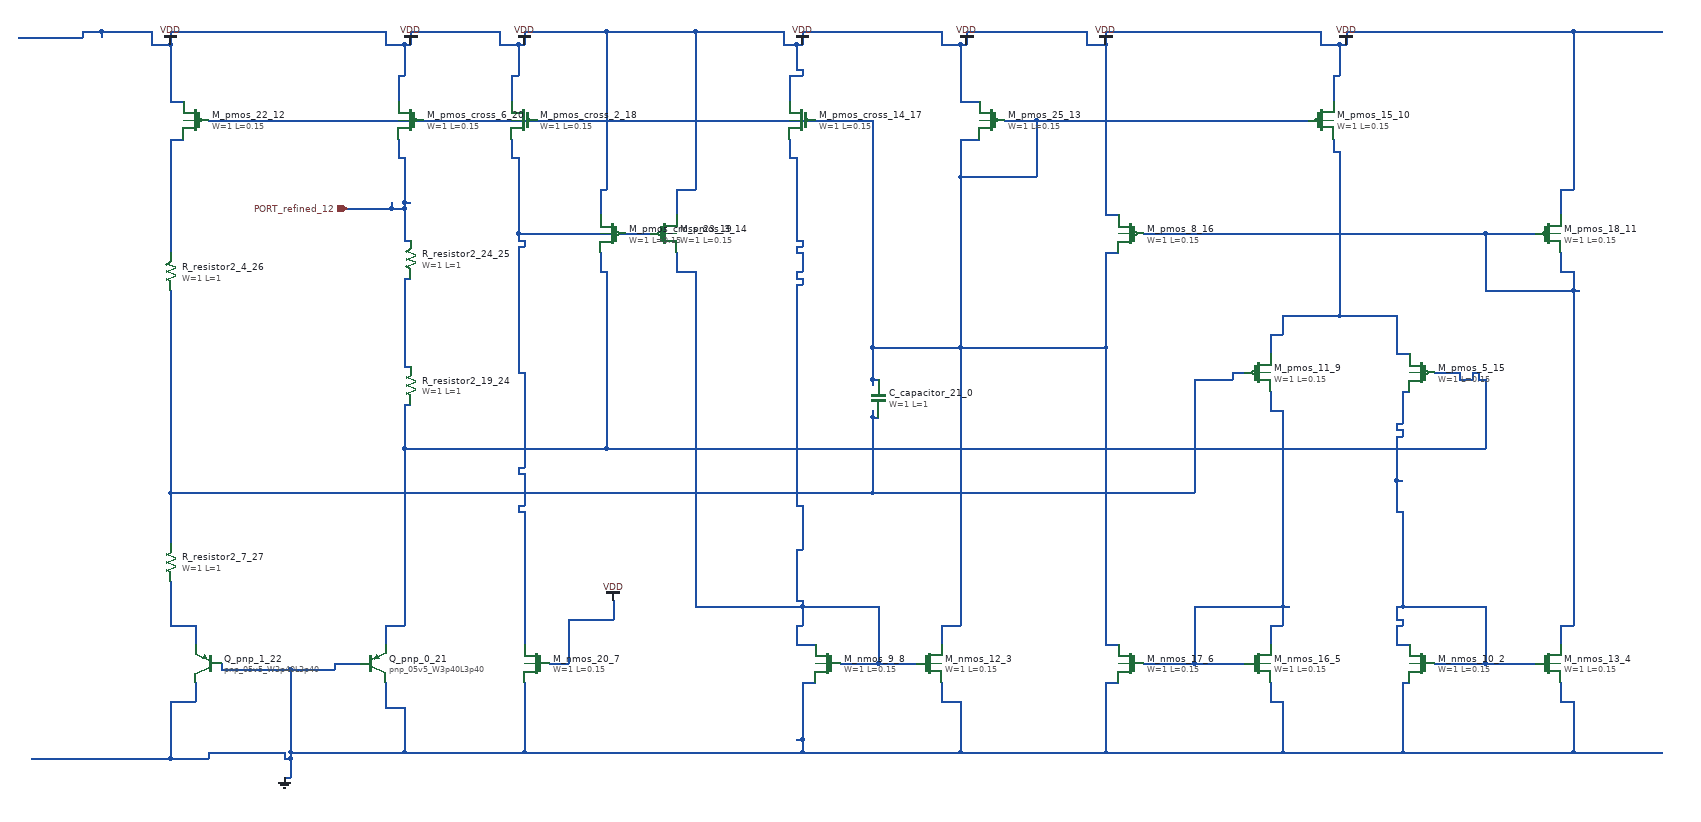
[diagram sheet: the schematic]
v {xschem version=3.4.8 file_version=1.2}
G {}
K {}
V {}
S {}
E {}
C {sky130_fd_pr/cap_mim_m3_1.sym} 1380 660 0 0 {name="C_capacitor_21_0" model=cap_mim_m3_1 W=1 L=1 MF=1 spiceprefix=X}
C {devices/gnd.sym} 440 1260 0 0 {name="l_gnd_26_1" lab="GND"}
C {sky130_fd_pr/nfet3_01v8.sym} 2240 1080 0 1 {name="M_nmos_10_2"
W=1
L=0.15
body=GND
nf=1
mult=1
ad="expr('int((@nf + 1)/2) * @W / @nf * 0.29')"
pd="expr('2*int((@nf + 1)/2) * (@W / @nf + 0.29)')"
as="expr('int((@nf + 2)/2) * @W / @nf * 0.29')"
ps="expr('2*int((@nf + 2)/2) * (@W / @nf + 0.29)')"
nrd="expr('0.29 / @W ')" nrs="expr('0.29 / @W ')"
sa=0 sb=0 sd=0
model=nfet_01v8
spiceprefix=X
}
C {sky130_fd_pr/nfet3_01v8.sym} 1460 1080 0 0 {name="M_nmos_12_3"
W=1
L=0.15
body=GND
nf=1
mult=1
ad="expr('int((@nf + 1)/2) * @W / @nf * 0.29')"
pd="expr('2*int((@nf + 1)/2) * (@W / @nf + 0.29)')"
as="expr('int((@nf + 2)/2) * @W / @nf * 0.29')"
ps="expr('2*int((@nf + 2)/2) * (@W / @nf + 0.29)')"
nrd="expr('0.29 / @W ')" nrs="expr('0.29 / @W ')"
sa=0 sb=0 sd=0
model=nfet_01v8
spiceprefix=X
}
C {sky130_fd_pr/nfet3_01v8.sym} 2440 1080 0 0 {name="M_nmos_13_4"
W=1
L=0.15
body=GND
nf=1
mult=1
ad="expr('int((@nf + 1)/2) * @W / @nf * 0.29')"
pd="expr('2*int((@nf + 1)/2) * (@W / @nf + 0.29)')"
as="expr('int((@nf + 2)/2) * @W / @nf * 0.29')"
ps="expr('2*int((@nf + 2)/2) * (@W / @nf + 0.29)')"
nrd="expr('0.29 / @W ')" nrs="expr('0.29 / @W ')"
sa=0 sb=0 sd=0
model=nfet_01v8
spiceprefix=X
}
C {sky130_fd_pr/nfet3_01v8.sym} 1980 1080 0 0 {name="M_nmos_16_5"
W=1
L=0.15
body=GND
nf=1
mult=1
ad="expr('int((@nf + 1)/2) * @W / @nf * 0.29')"
pd="expr('2*int((@nf + 1)/2) * (@W / @nf + 0.29)')"
as="expr('int((@nf + 2)/2) * @W / @nf * 0.29')"
ps="expr('2*int((@nf + 2)/2) * (@W / @nf + 0.29)')"
nrd="expr('0.29 / @W ')" nrs="expr('0.29 / @W ')"
sa=0 sb=0 sd=0
model=nfet_01v8
spiceprefix=X
}
C {sky130_fd_pr/nfet3_01v8.sym} 1780 1080 0 1 {name="M_nmos_17_6"
W=1
L=0.15
body=GND
nf=1
mult=1
ad="expr('int((@nf + 1)/2) * @W / @nf * 0.29')"
pd="expr('2*int((@nf + 1)/2) * (@W / @nf + 0.29)')"
as="expr('int((@nf + 2)/2) * @W / @nf * 0.29')"
ps="expr('2*int((@nf + 2)/2) * (@W / @nf + 0.29)')"
nrd="expr('0.29 / @W ')" nrs="expr('0.29 / @W ')"
sa=0 sb=0 sd=0
model=nfet_01v8
spiceprefix=X
}
C {sky130_fd_pr/nfet3_01v8.sym} 840 1080 0 1 {name="M_nmos_20_7"
W=1
L=0.15
body=GND
nf=1
mult=1
ad="expr('int((@nf + 1)/2) * @W / @nf * 0.29')"
pd="expr('2*int((@nf + 1)/2) * (@W / @nf + 0.29)')"
as="expr('int((@nf + 2)/2) * @W / @nf * 0.29')"
ps="expr('2*int((@nf + 2)/2) * (@W / @nf + 0.29)')"
nrd="expr('0.29 / @W ')" nrs="expr('0.29 / @W ')"
sa=0 sb=0 sd=0
model=nfet_01v8
spiceprefix=X
}
C {sky130_fd_pr/nfet3_01v8.sym} 1300 1080 0 1 {name="M_nmos_9_8"
W=1
L=0.15
body=GND
nf=1
mult=1
ad="expr('int((@nf + 1)/2) * @W / @nf * 0.29')"
pd="expr('2*int((@nf + 1)/2) * (@W / @nf + 0.29)')"
as="expr('int((@nf + 2)/2) * @W / @nf * 0.29')"
ps="expr('2*int((@nf + 2)/2) * (@W / @nf + 0.29)')"
nrd="expr('0.29 / @W ')" nrs="expr('0.29 / @W ')"
sa=0 sb=0 sd=0
model=nfet_01v8
spiceprefix=X
}
C {sky130_fd_pr/pfet3_01v8.sym} 1980 620 0 0 {name="M_pmos_11_9"
W=1
L=0.15
body=VDD
nf=1
mult=1
ad="expr('int((@nf + 1)/2) * @W / @nf * 0.29')"
pd="expr('2*int((@nf + 1)/2) * (@W / @nf + 0.29)')"
as="expr('int((@nf + 2)/2) * @W / @nf * 0.29')"
ps="expr('2*int((@nf + 2)/2) * (@W / @nf + 0.29)')"
nrd="expr('0.29 / @W ')" nrs="expr('0.29 / @W ')"
sa=0 sb=0 sd=0
model=pfet_01v8
spiceprefix=X
}
C {sky130_fd_pr/pfet3_01v8.sym} 2080 220 0 0 {name="M_pmos_15_10"
W=1
L=0.15
body=VDD
nf=1
mult=1
ad="expr('int((@nf + 1)/2) * @W / @nf * 0.29')"
pd="expr('2*int((@nf + 1)/2) * (@W / @nf + 0.29)')"
as="expr('int((@nf + 2)/2) * @W / @nf * 0.29')"
ps="expr('2*int((@nf + 2)/2) * (@W / @nf + 0.29)')"
nrd="expr('0.29 / @W ')" nrs="expr('0.29 / @W ')"
sa=0 sb=0 sd=0
model=pfet_01v8
spiceprefix=X
}
C {sky130_fd_pr/pfet3_01v8.sym} 2440 400 0 0 {name="M_pmos_18_11"
W=1
L=0.15
body=VDD
nf=1
mult=1
ad="expr('int((@nf + 1)/2) * @W / @nf * 0.29')"
pd="expr('2*int((@nf + 1)/2) * (@W / @nf + 0.29)')"
as="expr('int((@nf + 2)/2) * @W / @nf * 0.29')"
ps="expr('2*int((@nf + 2)/2) * (@W / @nf + 0.29)')"
nrd="expr('0.29 / @W ')" nrs="expr('0.29 / @W ')"
sa=0 sb=0 sd=0
model=pfet_01v8
spiceprefix=X
}
C {sky130_fd_pr/pfet3_01v8.sym} 300 220 0 1 {name="M_pmos_22_12"
W=1
L=0.15
body=VDD
nf=1
mult=1
ad="expr('int((@nf + 1)/2) * @W / @nf * 0.29')"
pd="expr('2*int((@nf + 1)/2) * (@W / @nf + 0.29)')"
as="expr('int((@nf + 2)/2) * @W / @nf * 0.29')"
ps="expr('2*int((@nf + 2)/2) * (@W / @nf + 0.29)')"
nrd="expr('0.29 / @W ')" nrs="expr('0.29 / @W ')"
sa=0 sb=0 sd=0
model=pfet_01v8
spiceprefix=X
}
C {sky130_fd_pr/pfet3_01v8.sym} 1560 220 0 1 {name="M_pmos_25_13"
W=1
L=0.15
body=VDD
nf=1
mult=1
ad="expr('int((@nf + 1)/2) * @W / @nf * 0.29')"
pd="expr('2*int((@nf + 1)/2) * (@W / @nf + 0.29)')"
as="expr('int((@nf + 2)/2) * @W / @nf * 0.29')"
ps="expr('2*int((@nf + 2)/2) * (@W / @nf + 0.29)')"
nrd="expr('0.29 / @W ')" nrs="expr('0.29 / @W ')"
sa=0 sb=0 sd=0
model=pfet_01v8
spiceprefix=X
}
C {sky130_fd_pr/pfet3_01v8.sym} 1040 400 0 0 {name="M_pmos_3_14"
W=1
L=0.15
body=VDD
nf=1
mult=1
ad="expr('int((@nf + 1)/2) * @W / @nf * 0.29')"
pd="expr('2*int((@nf + 1)/2) * (@W / @nf + 0.29)')"
as="expr('int((@nf + 2)/2) * @W / @nf * 0.29')"
ps="expr('2*int((@nf + 2)/2) * (@W / @nf + 0.29)')"
nrd="expr('0.29 / @W ')" nrs="expr('0.29 / @W ')"
sa=0 sb=0 sd=0
model=pfet_01v8
spiceprefix=X
}
C {sky130_fd_pr/pfet3_01v8.sym} 2240 620 0 1 {name="M_pmos_5_15"
W=1
L=0.15
body=VDD
nf=1
mult=1
ad="expr('int((@nf + 1)/2) * @W / @nf * 0.29')"
pd="expr('2*int((@nf + 1)/2) * (@W / @nf + 0.29)')"
as="expr('int((@nf + 2)/2) * @W / @nf * 0.29')"
ps="expr('2*int((@nf + 2)/2) * (@W / @nf + 0.29)')"
nrd="expr('0.29 / @W ')" nrs="expr('0.29 / @W ')"
sa=0 sb=0 sd=0
model=pfet_01v8
spiceprefix=X
}
C {sky130_fd_pr/pfet3_01v8.sym} 1780 400 0 1 {name="M_pmos_8_16"
W=1
L=0.15
body=VDD
nf=1
mult=1
ad="expr('int((@nf + 1)/2) * @W / @nf * 0.29')"
pd="expr('2*int((@nf + 1)/2) * (@W / @nf + 0.29)')"
as="expr('int((@nf + 2)/2) * @W / @nf * 0.29')"
ps="expr('2*int((@nf + 2)/2) * (@W / @nf + 0.29)')"
nrd="expr('0.29 / @W ')" nrs="expr('0.29 / @W ')"
sa=0 sb=0 sd=0
model=pfet_01v8
spiceprefix=X
}
C {sky130_fd_pr/pfet3_01v8.sym} 1260 220 0 1 {name="M_pmos_cross_14_17"
W=1
L=0.15
body=VDD
nf=1
mult=1
ad="expr('int((@nf + 1)/2) * @W / @nf * 0.29')"
pd="expr('2*int((@nf + 1)/2) * (@W / @nf + 0.29)')"
as="expr('int((@nf + 2)/2) * @W / @nf * 0.29')"
ps="expr('2*int((@nf + 2)/2) * (@W / @nf + 0.29)')"
nrd="expr('0.29 / @W ')" nrs="expr('0.29 / @W ')"
sa=0 sb=0 sd=0
model=pfet_01v8
spiceprefix=X
}
C {sky130_fd_pr/pfet3_01v8.sym} 820 220 0 1 {name="M_pmos_cross_2_18"
W=1
L=0.15
body=VDD
nf=1
mult=1
ad="expr('int((@nf + 1)/2) * @W / @nf * 0.29')"
pd="expr('2*int((@nf + 1)/2) * (@W / @nf + 0.29)')"
as="expr('int((@nf + 2)/2) * @W / @nf * 0.29')"
ps="expr('2*int((@nf + 2)/2) * (@W / @nf + 0.29)')"
nrd="expr('0.29 / @W ')" nrs="expr('0.29 / @W ')"
sa=0 sb=0 sd=0
model=pfet_01v8
spiceprefix=X
}
C {sky130_fd_pr/pfet3_01v8.sym} 960 400 0 1 {name="M_pmos_cross_23_19"
W=1
L=0.15
body=VDD
nf=1
mult=1
ad="expr('int((@nf + 1)/2) * @W / @nf * 0.29')"
pd="expr('2*int((@nf + 1)/2) * (@W / @nf + 0.29)')"
as="expr('int((@nf + 2)/2) * @W / @nf * 0.29')"
ps="expr('2*int((@nf + 2)/2) * (@W / @nf + 0.29)')"
nrd="expr('0.29 / @W ')" nrs="expr('0.29 / @W ')"
sa=0 sb=0 sd=0
model=pfet_01v8
spiceprefix=X
}
C {sky130_fd_pr/pfet3_01v8.sym} 640 220 0 1 {name="M_pmos_cross_6_20"
W=1
L=0.15
body=VDD
nf=1
mult=1
ad="expr('int((@nf + 1)/2) * @W / @nf * 0.29')"
pd="expr('2*int((@nf + 1)/2) * (@W / @nf + 0.29)')"
as="expr('int((@nf + 2)/2) * @W / @nf * 0.29')"
ps="expr('2*int((@nf + 2)/2) * (@W / @nf + 0.29)')"
nrd="expr('0.29 / @W ')" nrs="expr('0.29 / @W ')"
sa=0 sb=0 sd=0
model=pfet_01v8
spiceprefix=X
}
C {sky130_fd_pr/pnp_05v5.sym} 580 1080 0 0 {name="Q_pnp_0_21"
model=pnp_05v5_W3p40L3p40
m=1
spiceprefix=X
}
C {sky130_fd_pr/pnp_05v5.sym} 320 1080 0 1 {name="Q_pnp_1_22"
model=pnp_05v5_W3p40L3p40
m=1
spiceprefix=X
}
C {devices/ipin.sym} 540 360 0 0 {name="p_port_27_23" lab="PORT_refined_12"}
C {sky130_fd_pr/res_generic_po.sym} 640 640 2 0 {name="R_resistor2_19_24"
W=1
L=1
model=res_generic_po
spiceprefix=X
mult=1}
C {sky130_fd_pr/res_generic_po.sym} 640 440 2 0 {name="R_resistor2_24_25"
W=1
L=1
model=res_generic_po
spiceprefix=X
mult=1}
C {sky130_fd_pr/res_generic_po.sym} 260 460 2 0 {name="R_resistor2_4_26"
W=1
L=1
model=res_generic_po
spiceprefix=X
mult=1}
C {sky130_fd_pr/res_generic_po.sym} 260 920 2 0 {name="R_resistor2_7_27"
W=1
L=1
model=res_generic_po
spiceprefix=X
mult=1}
C {devices/vdd.sym} 1260 100 0 0 {name="l_vdd_28_28" lab="VDD"}
C {devices/vdd.sym} 640 100 0 0 {name="l_vdd_29_29" lab="VDD"}
C {devices/vdd.sym} 820 100 0 0 {name="l_vdd_30_30" lab="VDD"}
C {devices/vdd.sym} 260 100 0 0 {name="l_vdd_31_31" lab="VDD"}
C {devices/vdd.sym} 1520 100 0 0 {name="l_vdd_32_32" lab="VDD"}
C {devices/vdd.sym} 2120 100 0 0 {name="l_vdd_33_33" lab="VDD"}
C {devices/vdd.sym} 960 980 0 0 {name="l_vdd_34_34" lab="VDD"}
C {devices/vdd.sym} 1740 100 0 0 {name="l_vdd_35_35" lab="VDD"}
N 260 810 1370 810 {}
N 1370 810 1880 810 {}
N 1370 690 1380 690 {}
N 1880 630 1940 630 {}
N 1940 620 1960 620 {}
N 260 890 260 810 {}
N 260 810 260 490 {}
N 1370 810 1370 690 {}
N 1370 690 1370 680 {}
N 1880 810 1880 630 {}
N 1940 630 1940 620 {}
N 1740 1050 1760 1050 {}
N 1480 1020 1510 1020 {}
N 1370 630 1380 630 {}
N 1370 580 1510 580 {}
N 1510 580 1740 580 {}
N 1740 430 1760 430 {}
N 1510 310 1630 310 {}
N 1510 250 1540 250 {}
N 320 220 660 220 {}
N 660 220 840 220 {}
N 840 220 1280 220 {}
N 1280 220 1370 220 {}
N 1580 220 1630 220 {}
N 1630 220 2060 220 {}
N 1370 640 1370 630 {}
N 1370 630 1370 580 {}
N 1370 580 1370 220 {}
N 1480 1050 1480 1020 {}
N 1510 1020 1510 580 {}
N 1510 580 1510 310 {}
N 1510 310 1510 250 {}
N 1630 310 1630 220 {}
N 1740 1050 1740 580 {}
N 1740 580 1740 430 {}
N 260 250 280 250 {}
N 260 430 260 250 {}
N 600 1020 630 1020 {}
N 630 740 950 740 {}
N 950 740 2340 740 {}
N 630 670 640 670 {}
N 2300 630 2320 630 {}
N 2330 630 2340 630 {}
N 2260 620 2300 620 {}
N 2320 620 2330 620 {}
N 940 460 950 460 {}
N 600 1050 600 1020 {}
N 630 1020 630 740 {}
N 630 740 630 670 {}
N 940 460 940 430 {}
N 950 740 950 460 {}
N 2300 630 2300 620 {}
N 2320 630 2320 620 {}
N 2330 630 2330 620 {}
N 2340 740 2340 630 {}
N 630 410 640 410 {}
N 540 360 610 360 {}
N 610 360 630 360 {}
N 630 350 640 350 {}
N 620 280 630 280 {}
N 610 360 610 350 {}
N 620 280 620 250 {}
N 630 410 630 360 {}
N 630 360 630 350 {}
N 630 350 630 280 {}
N 260 1020 300 1020 {}
N 260 1020 260 950 {}
N 300 1050 300 1020 {}
N 630 610 640 610 {}
N 630 470 640 470 {}
N 630 610 630 470 {}
N 440 1260 450 1260 {}
N 40 1230 260 1230 {}
N 260 1230 320 1230 {}
N 440 1230 450 1230 {}
N 320 1220 440 1220 {}
N 450 1220 630 1220 {}
N 630 1220 820 1220 {}
N 820 1220 1260 1220 {}
N 1260 1220 1510 1220 {}
N 1510 1220 1740 1220 {}
N 1740 1220 2020 1220 {}
N 2020 1220 2210 1220 {}
N 2210 1220 2480 1220 {}
N 2480 1220 2620 1220 {}
N 1250 1200 1260 1200 {}
N 600 1150 630 1150 {}
N 260 1140 300 1140 {}
N 1480 1140 1510 1140 {}
N 2000 1140 2020 1140 {}
N 2460 1140 2480 1140 {}
N 1260 1110 1280 1110 {}
N 1740 1110 1760 1110 {}
N 2210 1110 2220 1110 {}
N 340 1090 450 1090 {}
N 450 1090 520 1090 {}
N 520 1080 560 1080 {}
N 260 1230 260 1140 {}
N 300 1140 300 1110 {}
N 320 1230 320 1220 {}
N 340 1090 340 1080 {}
N 440 1230 440 1220 {}
N 450 1260 450 1230 {}
N 450 1230 450 1220 {}
N 450 1220 450 1090 {}
N 520 1090 520 1080 {}
N 600 1150 600 1110 {}
N 630 1220 630 1150 {}
N 820 1220 820 1110 {}
N 1260 1220 1260 1200 {}
N 1260 1200 1260 1110 {}
N 1480 1140 1480 1110 {}
N 1510 1220 1510 1140 {}
N 1740 1220 1740 1110 {}
N 2000 1140 2000 1110 {}
N 2020 1220 2020 1140 {}
N 2210 1220 2210 1110 {}
N 2460 1140 2460 1110 {}
N 2480 1220 2480 1140 {}
N 2260 1080 2340 1080 {}
N 2340 1080 2420 1080 {}
N 2200 1050 2220 1050 {}
N 2200 1020 2210 1020 {}
N 2200 1010 2210 1010 {}
N 2200 990 2210 990 {}
N 2210 990 2340 990 {}
N 2200 840 2210 840 {}
N 2200 790 2210 790 {}
N 2200 720 2210 720 {}
N 2200 710 2210 710 {}
N 2200 700 2210 700 {}
N 2210 650 2220 650 {}
N 2200 1050 2200 1020 {}
N 2200 1010 2200 990 {}
N 2200 840 2200 790 {}
N 2200 790 2200 720 {}
N 2200 710 2200 700 {}
N 2210 1020 2210 1010 {}
N 2210 990 2210 840 {}
N 2210 720 2210 710 {}
N 2210 700 2210 650 {}
N 2340 1080 2340 990 {}
N 1800 1080 1880 1080 {}
N 1880 1080 1960 1080 {}
N 2000 1020 2020 1020 {}
N 1880 990 2020 990 {}
N 2020 990 2030 990 {}
N 2000 680 2020 680 {}
N 1880 1080 1880 990 {}
N 2000 1050 2000 1020 {}
N 2000 680 2000 650 {}
N 2020 1020 2020 990 {}
N 2020 990 2020 680 {}
N 810 840 820 840 {}
N 810 830 820 830 {}
N 810 780 820 780 {}
N 810 770 820 770 {}
N 810 620 820 620 {}
N 810 420 820 420 {}
N 810 410 820 410 {}
N 810 400 980 400 {}
N 980 400 1020 400 {}
N 800 280 810 280 {}
N 800 280 800 250 {}
N 810 840 810 830 {}
N 810 780 810 770 {}
N 810 620 810 420 {}
N 810 410 810 400 {}
N 810 400 810 280 {}
N 820 1050 820 840 {}
N 820 830 820 780 {}
N 820 770 820 620 {}
N 820 420 820 410 {}
N 1320 1080 1380 1080 {}
N 1380 1080 1440 1080 {}
N 1250 1050 1280 1050 {}
N 1250 1020 1260 1020 {}
N 1090 990 1260 990 {}
N 1260 990 1380 990 {}
N 1250 980 1260 980 {}
N 1250 900 1260 900 {}
N 1250 830 1260 830 {}
N 1250 480 1260 480 {}
N 1250 470 1260 470 {}
N 1060 460 1090 460 {}
N 1250 460 1260 460 {}
N 1250 430 1260 430 {}
N 1250 420 1260 420 {}
N 1250 410 1260 410 {}
N 1240 280 1250 280 {}
N 1060 460 1060 430 {}
N 1090 990 1090 460 {}
N 1240 280 1240 250 {}
N 1250 1050 1250 1020 {}
N 1250 980 1250 900 {}
N 1250 830 1250 480 {}
N 1250 470 1250 460 {}
N 1250 430 1250 420 {}
N 1250 410 1250 280 {}
N 1260 1020 1260 990 {}
N 1260 990 1260 980 {}
N 1260 900 1260 830 {}
N 1260 480 1260 470 {}
N 1260 460 1260 430 {}
N 1260 420 1260 410 {}
N 1380 1080 1380 990 {}
N 2200 590 2220 590 {}
N 2000 560 2020 560 {}
N 2020 530 2110 530 {}
N 2110 530 2200 530 {}
N 2100 270 2110 270 {}
N 2000 590 2000 560 {}
N 2020 560 2020 530 {}
N 2100 270 2100 250 {}
N 2110 530 2110 270 {}
N 2200 590 2200 530 {}
N 860 1080 890 1080 {}
N 890 1010 960 1010 {}
N 1740 370 1760 370 {}
N 940 330 950 330 {}
N 1060 330 1090 330 {}
N 2460 330 2480 330 {}
N 260 190 280 190 {}
N 1510 190 1540 190 {}
N 620 150 630 150 {}
N 800 150 810 150 {}
N 1240 150 1260 150 {}
N 2100 150 2110 150 {}
N 1250 140 1260 140 {}
N 230 100 260 100 {}
N 600 100 630 100 {}
N 630 100 640 100 {}
N 780 100 810 100 {}
N 810 100 820 100 {}
N 1230 100 1250 100 {}
N 1250 100 1260 100 {}
N 1480 100 1510 100 {}
N 1510 100 1520 100 {}
N 1710 100 1740 100 {}
N 2080 100 2110 100 {}
N 2110 100 2120 100 {}
N 20 90 120 90 {}
N 120 80 150 80 {}
N 150 80 230 80 {}
N 260 80 600 80 {}
N 640 80 780 80 {}
N 820 80 950 80 {}
N 950 80 1090 80 {}
N 1090 80 1230 80 {}
N 1260 80 1480 80 {}
N 1520 80 1710 80 {}
N 1740 80 2080 80 {}
N 2120 80 2480 80 {}
N 2480 80 2620 80 {}
N 120 90 120 80 {}
N 150 90 150 80 {}
N 230 100 230 80 {}
N 260 190 260 100 {}
N 260 100 260 80 {}
N 600 100 600 80 {}
N 620 190 620 150 {}
N 630 150 630 100 {}
N 640 100 640 80 {}
N 780 100 780 80 {}
N 800 190 800 150 {}
N 810 150 810 100 {}
N 820 100 820 80 {}
N 890 1080 890 1010 {}
N 940 370 940 330 {}
N 950 330 950 80 {}
N 960 1010 960 980 {}
N 1060 370 1060 330 {}
N 1090 330 1090 80 {}
N 1230 100 1230 80 {}
N 1240 190 1240 150 {}
N 1250 140 1250 100 {}
N 1260 150 1260 140 {}
N 1260 100 1260 80 {}
N 1480 100 1480 80 {}
N 1510 190 1510 100 {}
N 1520 100 1520 80 {}
N 1710 100 1710 80 {}
N 1740 370 1740 100 {}
N 1740 100 1740 80 {}
N 2080 100 2080 80 {}
N 2100 190 2100 150 {}
N 2110 150 2110 100 {}
N 2120 100 2120 80 {}
N 2460 370 2460 330 {}
N 2480 330 2480 80 {}
N 2460 1020 2480 1020 {}
N 2340 490 2480 490 {}
N 2480 490 2490 490 {}
N 2460 460 2480 460 {}
N 1800 400 2340 400 {}
N 2340 400 2420 400 {}
N 2340 490 2340 400 {}
N 2460 1050 2460 1020 {}
N 2460 460 2460 430 {}
N 2480 1020 2480 490 {}
N 2480 490 2480 460 {}
